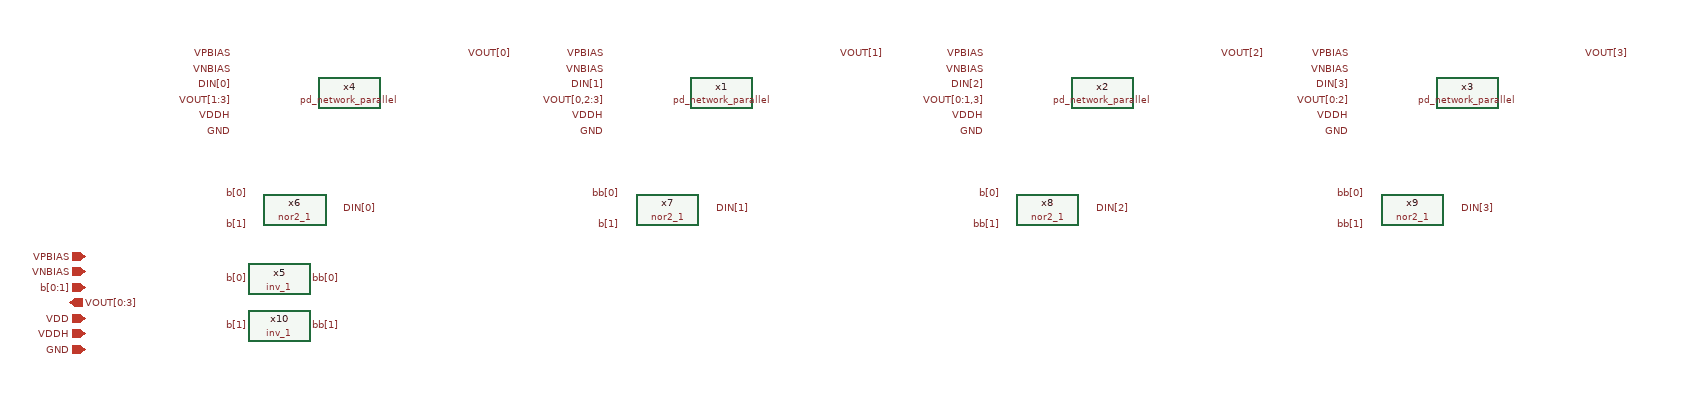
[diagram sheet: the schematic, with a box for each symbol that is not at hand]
v {xschem version=3.4.6 file_version=1.2}
G {}
K {}
V {}
S {}
E {}
C {devices/title.sym} 160 -40 0 0 {name=l1 author="Yohanes Stefanus"}
C {devices/lab_pin.sym} 260 -530 0 0 {name=p4 sig_type=std_logic lab=VPBIAS}
C {devices/lab_pin.sym} 260 -510 0 0 {name=p1 sig_type=std_logic lab=VNBIAS}
C {devices/lab_pin.sym} 260 -490 0 0 {name=p2 sig_type=std_logic lab=DIN[0]}
C {devices/lab_pin.sym} 260 -470 0 0 {name=p3 sig_type=std_logic lab=VOUT[1:3]}
C {devices/lab_pin.sym} 260 -450 0 0 {name=p5 sig_type=std_logic lab=VDDH}
C {devices/lab_pin.sym} 260 -430 0 0 {name=p6 sig_type=std_logic lab=GND}
C {devices/lab_pin.sym} 560 -530 0 1 {name=p17 sig_type=std_logic lab=VOUT[0]}
C {devices/lab_pin.sym} 740 -530 0 0 {name=p9 sig_type=std_logic lab=VPBIAS}
C {devices/lab_pin.sym} 740 -510 0 0 {name=p10 sig_type=std_logic lab=VNBIAS}
C {devices/lab_pin.sym} 740 -490 0 0 {name=p11 sig_type=std_logic lab=DIN[1]}
C {devices/lab_pin.sym} 740 -470 0 0 {name=p12 sig_type=std_logic lab=VOUT[0,2:3]}
C {devices/lab_pin.sym} 740 -450 0 0 {name=p13 sig_type=std_logic lab=VDDH}
C {devices/lab_pin.sym} 740 -430 0 0 {name=p14 sig_type=std_logic lab=GND}
C {devices/lab_pin.sym} 1040 -530 0 1 {name=p18 sig_type=std_logic lab=VOUT[1]}
C {devices/lab_pin.sym} 1230 -530 0 0 {name=p19 sig_type=std_logic lab=VPBIAS}
C {devices/lab_pin.sym} 1230 -510 0 0 {name=p20 sig_type=std_logic lab=VNBIAS}
C {devices/lab_pin.sym} 1230 -490 0 0 {name=p21 sig_type=std_logic lab=DIN[2]}
C {devices/lab_pin.sym} 1230 -470 0 0 {name=p22 sig_type=std_logic lab=VOUT[0:1,3]}
C {devices/lab_pin.sym} 1230 -450 0 0 {name=p23 sig_type=std_logic lab=VDDH}
C {devices/lab_pin.sym} 1230 -430 0 0 {name=p24 sig_type=std_logic lab=GND}
C {devices/lab_pin.sym} 1530 -530 0 1 {name=p27 sig_type=std_logic lab=VOUT[2]}
C {devices/lab_pin.sym} 1700 -530 0 0 {name=p28 sig_type=std_logic lab=VPBIAS}
C {devices/lab_pin.sym} 1700 -510 0 0 {name=p29 sig_type=std_logic lab=VNBIAS}
C {devices/lab_pin.sym} 1700 -490 0 0 {name=p30 sig_type=std_logic lab=DIN[3]}
C {devices/lab_pin.sym} 1700 -470 0 0 {name=p31 sig_type=std_logic lab=VOUT[0:2]}
C {devices/lab_pin.sym} 1700 -450 0 0 {name=p32 sig_type=std_logic lab=VDDH}
C {devices/lab_pin.sym} 1700 -430 0 0 {name=p33 sig_type=std_logic lab=GND}
C {devices/lab_pin.sym} 2000 -530 0 1 {name=p36 sig_type=std_logic lab=VOUT[3]}
C {devices/ipin.sym} 70 -270 0 0 {name=p37 lab=VPBIAS}
C {devices/ipin.sym} 70 -250 0 0 {name=p38 lab=VNBIAS}
C {devices/ipin.sym} 70 -230 0 0 {name=p39 lab=b[0:1]}
C {devices/opin.sym} 50 -210 0 0 {name=p41 lab=VOUT[0:3]}
C {devices/ipin.sym} 70 -170 0 0 {name=p42 lab=VDDH}
C {devices/ipin.sym} 70 -150 0 0 {name=p43 lab=GND}
C {devices/lab_pin.sym} 280 -240 0 0 {name=p46 sig_type=std_logic lab=b[0]}
C {devices/lab_pin.sym} 280 -180 0 0 {name=p47 sig_type=std_logic lab=b[1]}
C {devices/lab_pin.sym} 360 -240 0 1 {name=p48 sig_type=std_logic lab=bb[0]}
C {devices/lab_pin.sym} 360 -180 0 1 {name=p49 sig_type=std_logic lab=bb[1]}
C {devices/lab_pin.sym} 400 -330 0 1 {name=p56 sig_type=std_logic lab=DIN[0]}
C {devices/lab_pin.sym} 880 -330 0 1 {name=p57 sig_type=std_logic lab=DIN[1]}
C {devices/lab_pin.sym} 1370 -330 0 1 {name=p58 sig_type=std_logic lab=DIN[2]}
C {devices/lab_pin.sym} 1840 -330 0 1 {name=p59 sig_type=std_logic lab=DIN[3]}
C {devices/lab_pin.sym} 280 -350 0 0 {name=p40 sig_type=std_logic lab=b[0]}
C {devices/lab_pin.sym} 280 -310 0 0 {name=p66 sig_type=std_logic lab=b[1]}
C {devices/lab_pin.sym} 760 -350 0 0 {name=p67 sig_type=std_logic lab=bb[0]}
C {devices/lab_pin.sym} 760 -310 0 0 {name=p68 sig_type=std_logic lab=b[1]}
C {devices/lab_pin.sym} 1250 -350 0 0 {name=p69 sig_type=std_logic lab=b[0]}
C {devices/lab_pin.sym} 1250 -310 0 0 {name=p70 sig_type=std_logic lab=bb[1]}
C {devices/lab_pin.sym} 1720 -350 0 0 {name=p71 sig_type=std_logic lab=bb[0]}
C {devices/lab_pin.sym} 1720 -310 0 0 {name=p72 sig_type=std_logic lab=bb[1]}
C {devices/ipin.sym} 70 -190 0 0 {name=p62 lab=VDD}
C {sky130_stdcells/inv_1.sym} 320 -240 0 0 {name=x5 VGND=GND VNB=GND VPB=VDD VPWR=VDD prefix=sky130_fd_sc_hd__ }
C {sky130_stdcells/inv_1.sym} 320 -180 0 0 {name=x10 VGND=GND VNB=GND VPB=VDD VPWR=VDD prefix=sky130_fd_sc_hd__ }
C {pd_network_parallel.sym} 890 -480 0 0 {name=x1}
C {pd_network_parallel.sym} 1380 -480 0 0 {name=x2}
C {pd_network_parallel.sym} 1850 -480 0 0 {name=x3}
C {pd_network_parallel.sym} 410 -480 0 0 {name=x4}
C {sky130_stdcells/nor2_1.sym} 340 -330 0 0 {name=x6 VGND=GND VNB=GND VPB=VDD VPWR=VDD prefix=sky130_fd_sc_hd__ }
C {sky130_stdcells/nor2_1.sym} 820 -330 0 0 {name=x7 VGND=GND VNB=GND VPB=VDD VPWR=VDD prefix=sky130_fd_sc_hd__ }
C {sky130_stdcells/nor2_1.sym} 1310 -330 0 0 {name=x8 VGND=GND VNB=GND VPB=VDD VPWR=VDD prefix=sky130_fd_sc_hd__ }
C {sky130_stdcells/nor2_1.sym} 1780 -330 0 0 {name=x9 VGND=GND VNB=GND VPB=VDD VPWR=VDD prefix=sky130_fd_sc_hd__ }
